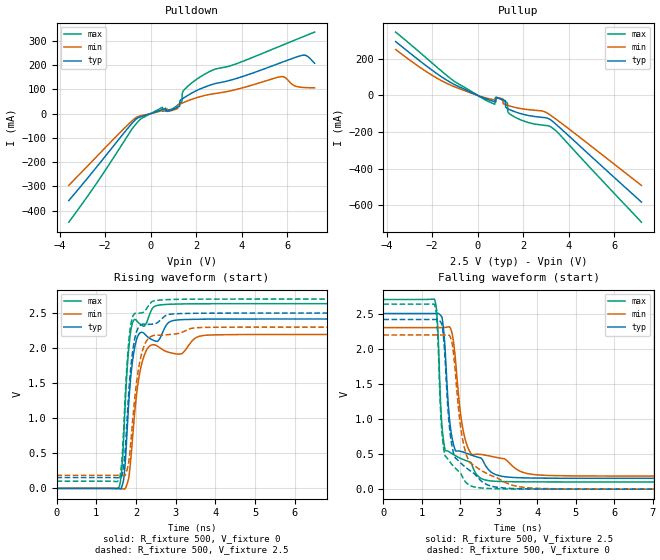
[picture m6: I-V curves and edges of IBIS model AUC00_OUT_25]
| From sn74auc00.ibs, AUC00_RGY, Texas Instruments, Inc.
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[Model]   AUC00_OUT_25
Model_type  Output
Vref =   0
Rref =   500
Cref =   30p
Vmeas =   1.25
| variable   typ   min   max
C_comp   7.46pF   0.24pF   23.67pF
| C_pullup   8.38pF   0.24pF   23.67pF
| C_pulldown   6.55pF   1.87pF   15.80pF
[Temperature Range]   40   100   -40
| Ambient temperature   25   85   -40
[Voltage range]   2.5   2.3   2.7
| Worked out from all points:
|   slope of the pulldown table from 0 to 0.375 V, typ, clamps not added: 30.9 ohm
|   slope of the pullup table from 0 to 0.375 V, typ, clamps not added: 19.2 ohm
|   rising waveform, R_fixture 500, V_fixture 0: 20-80 % time 201ps typ, 264ps min, 165ps max; typ from 0 V to 2.42 V
|   falling waveform, R_fixture 500, V_fixture 2.5: 20-80 % time 229ps typ, 316ps min, 160ps max; typ from 2.5 V to 0.154 V
|   rising waveform, R_fixture 500, V_fixture 2.5: 20-80 % time 198ps typ, 262ps min, 164ps max; typ from 0.154 V to 2.5 V
|   falling waveform, R_fixture 500, V_fixture 0: 20-80 % time 244ps typ, 338ps min, 162ps max; typ from 2.42 V to 0 V
[Pulldown]
| AUC00_OUT_25
|   Voltage   I(typ)   I(min)   I(max)
-3.6V     -358mA     -295.2mA   -447mA
-445mV    -13.39mA   -9.086mA   -23.04mA
515mV     17.02mA    12.57mA    25.99mA
1.025V    18.9mA     15.4mA     23.61mA
1.27V     30.1mA     38.43mA    41.47mA
1.37V     59.42mA    42.49mA    49.07mA
1.395V    60.94mA    43.5mA     85.27mA
1.48V     66.06mA    46.86mA    98.94mA
2.545V    115mA      77.99mA    170.9mA
5.695V    208.5mA    151.5mA    277.9mA
6.74V     240.5mA    107.2mA    317.9mA
7.2V      207mA      105.9mA    335.2mA
[Pullup]
| AUC00_OUT_25
|   Voltage   I(typ)   I(min)   I(max)
-3.6V     293.6mA    250.5mA    345.5mA
-960mV    55.5mA     44.14mA    71.53mA
730mV     -33.82mA   -24.42mA   -47.21mA
760mV     -34.84mA   -25.13mA   -47.16mA
770mV     -35.18mA   -25.36mA   -13.07mA
1.115V    -23.95mA   -20.34mA   -27.78mA
1.215V    -28.93mA   -50.57mA   -34.8mA
1.295V    -71.17mA   -53.86mA   -40.35mA
1.345V    -74.43mA   -55.82mA   -93.46mA
1.755V    -94.55mA   -68.88mA   -126.2mA
3.31V     -143.6mA   -118mA     -180.5mA
7.2V      -582.9mA   -492mA     -692.7mA
[Ramp]
| AUC00_OUT_25
| variable   typ   min   max
dV/dt_r   1.45/2.03E-10   1.32/2.65E-10   1.59/1.67E-10
dV/dt_f   1.41/2.30E-10   1.28/3.18E-10   1.56/1.62E-10
R_load = 500
[Rising Waveform]
| AUC00_OUT_25
R_fixture =   500
C_fixture =   0
L_fixture =   0
V_fixture =   0
V_fixture_min = 0
V_fixture_max = 0
|   Time   V(typ)   V(min)   V(max)
0s        9.791nV    28.67nV    1.858nV
1.58ns    -4.665mV   -935.2uV   22.55mV
1.645ns   24.84mV    -4.208mV   265.2mV
1.705ns   198.3mV    -9.379mV   888.5mV
1.79ns    941.1mV    85.17mV    1.79V
1.89ns    1.699V     542.2mV    2.308V
2.145ns   2.226V     1.773V     2.328V
2.54ns    2.097V     2.03V      2.609V
3.26ns    2.408V     1.984V     2.631V
20ns      2.416V     2.195V     2.634V
[Falling Waveform]
| AUC00_OUT_25
R_fixture =   500
C_fixture =   0
L_fixture =   0
V_fixture =   2.5
V_fixture_min = 2.3
V_fixture_max = 2.7
|   Time   V(typ)   V(min)   V(max)
0s        2.5V       2.3V       2.7V
1.33ns    2.501V     2.3V       2.702V
1.4ns     2.502V     2.3V       2.419V
1.525ns   2.446V     2.3V       888.2mV
1.6ns     2.032V     2.303V     566.6mV
1.715ns   1.018V     2.312V     530.1mV
1.855ns   575.3mV    1.947V     481.9mV
2.15ns    513.1mV    664.7mV    406.1mV
2.67ns    322.8mV    482mV      127.7mV
20ns      154.5mV    186.3mV    102.6mV
[Rising Waveform]
| AUC00_OUT_25
R_fixture =   500
C_fixture =   0
L_fixture =   0
V_fixture =   2.5
V_fixture_min = 2.3
V_fixture_max = 2.7
|   Time   V(typ)   V(min)   V(max)
0s        154.5mV    186.3mV    102.6mV
1.58ns    151.3mV    185.4mV    127.1mV
1.645ns   186.5mV    183mV      385.7mV
1.7ns     348.6mV    180.7mV    951.5mV
1.79ns    1.109V     295.8mV    1.886V
1.88ns    1.775V     720.2mV    2.364V
1.985ns   2.173V     1.366V     2.497V
2.12ns    2.331V     1.865V     2.501V
2.46ns    2.345V     2.183V     2.675V
20ns      2.5V       2.3V       2.7V
[Falling Waveform]
| AUC00_OUT_25
R_fixture =   500
C_fixture =   0
L_fixture =   0
V_fixture =   0
V_fixture_min = 0
V_fixture_max = 0
|   Time   V(typ)   V(min)   V(max)
0s        2.416V     2.195V     2.634V
1.33ns    2.416V     2.195V     2.629V
1.39ns    2.415V     2.195V     2.414V
1.59ns    1.972V     2.195V     501.8mV
1.7ns     984.6mV    2.192V     409.3mV
1.82ns    522.2mV    1.946V     327.7mV
2.06ns    347.1mV    708.5mV    168.9mV
2.37ns    216.3mV    330.6mV    30.3mV
4.115ns   2.029mV    9.437mV    495.1uV
20ns      23.68uV    3.157uV    10.98uV
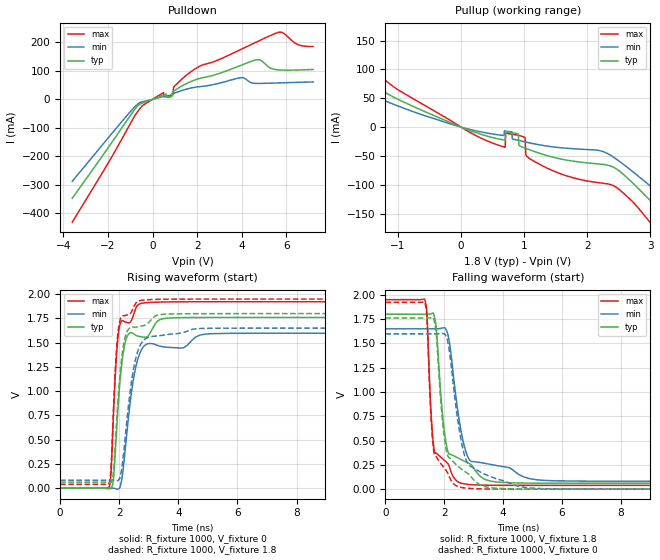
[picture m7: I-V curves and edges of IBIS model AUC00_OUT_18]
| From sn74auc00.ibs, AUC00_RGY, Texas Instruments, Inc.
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[Model]   AUC00_OUT_18
Model_type  Output
Vref =   0
Rref =   1000
Cref =   30p
Vmeas =   0.9
| variable   typ   min   max
C_comp   6.70pF   0.46pF   21.41pF
| C_pullup   7.16pF   1.06pF   21.41pF
| C_pulldown   6.24pF   0.46pF   15.47pF
[Temperature Range]   40   100   -40
| Ambient temperature   25   85   -40
[Voltage range]   1.8   1.65   1.95
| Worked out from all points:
|   slope of the pulldown table from 0 to 0.27 V, typ, clamps not added: 34.4 ohm
|   slope of the pullup table from 0 to 0.27 V, typ, clamps not added: 24.7 ohm
|   rising waveform, R_fixture 1000, V_fixture 0: 20-80 % time 278ps typ, 406ps min, 195ps max; typ from 0 V to 1.76 V
|   falling waveform, R_fixture 1000, V_fixture 1.8: 20-80 % time 326ps typ, 475ps min, 204ps max; typ from 1.8 V to 0.061 V
|   rising waveform, R_fixture 1000, V_fixture 1.8: 20-80 % time 274ps typ, 398ps min, 191ps max; typ from 0.061 V to 1.8 V
|   falling waveform, R_fixture 1000, V_fixture 0: 20-80 % time 335ps typ, 485ps min, 204ps max; typ from 1.76 V to 0 V
[Pulldown]
| AUC00_OUT_18
|   Voltage   I(typ)   I(min)   I(max)
-3.6V     -347.8mA   -287.9mA   -431.3mA
-830mV    -38.95mA   -28.95mA   -62.23mA
-405mV    -11.33mA   -7.446mA   -19.55mA
495mV     14.95mA    10.62mA    23.51mA
885mV     12.29mA    19.09mA    15.87mA
925mV     28.57mA    20.19mA    16.9mA
960mV     30.15mA    21.18mA    44.34mA
2.04V     71.84mA    43.97mA    113.3mA
3.92V     118.2mA    75.86mA    173.7mA
4.62V     138.3mA    56mA       199.9mA
5.58V     103.9mA    57.61mA    233.8mA
7.2V      105mA      61.31mA    185.3mA
[Pullup]
| AUC00_OUT_18
|   Voltage   I(typ)   I(min)   I(max)
-3.6V     267.6mA    221.5mA    318.7mA
-2.61V    174.3mA    138.3mA    219.8mA
-2.13V    131.5mA    101.8mA    171.7mA
110mV     -4.812mA   -3.244mA   -7.318mA
695mV     -22.64mA   -6.828mA   -34.84mA
705mV     -8.169mA   -6.943mA   -10.57mA
975mV     -34.74mA   -24.57mA   -16.33mA
1.11V     -40.27mA   -27.85mA   -56.21mA
2.25V     -64.64mA   -42.32mA   -97.32mA
3.1V      -138.7mA   -111.4mA   -179.7mA
3.92V     -231.1mA   -188.5mA   -290.4mA
7.2V      -598.2mA   -503.5mA   -721.3mA
[Ramp]
| AUC00_OUT_18
| variable   typ   min   max
dV/dt_r   1.06/2.80E-10   0.97/4.09E-10   1.16/1.97E-10
dV/dt_f   1.05/3.30E-10   0.95/4.81E-10   1.15/2.09E-10
R_load = 1000
[Rising Waveform]
| AUC00_OUT_18
R_fixture =   1000
C_fixture =   0
L_fixture =   0
V_fixture =   0
V_fixture_min = 0
V_fixture_max = 0
|   Time   V(typ)   V(min)   V(max)
0s        7.669nV    26.14nV    1.117nV
1.65ns    -2.946mV   534.2uV    7.49mV
1.725ns   -7.074mV   433.3uV    178.9mV
1.8ns     83.25mV    -1.437mV   725mV
1.995ns   989.9mV    -2.596mV   1.644V
2.25ns    1.552V     547mV      1.71V
2.475ns   1.594V     1.115V     1.78V
2.72ns    1.562V     1.407V     1.904V
3.81ns    1.756V     1.449V     1.921V
20ns      1.761V     1.597V     1.922V
[Falling Waveform]
| AUC00_OUT_18
R_fixture =   1000
C_fixture =   0
L_fixture =   0
V_fixture =   1.8
V_fixture_min = 1.65
V_fixture_max = 1.95
|   Time   V(typ)   V(min)   V(max)
0s        1.8V       1.65V      1.95V
1.335ns   1.8V       1.65V      1.953V
1.405ns   1.8V       1.65V      1.835V
1.55ns    1.804V     1.65V      799.3mV
1.665ns   1.776V     1.65V      393.8mV
2.075ns   452.5mV    1.635V     278.2mV
2.56ns    305.8mV    617.3mV    63.36mV
2.905ns   254.4mV    287.8mV    46.79mV
5.16ns    61.98mV    96.08mV    38.83mV
20ns      61.08mV    81.21mV    38.69mV
[Rising Waveform]
| AUC00_OUT_18
R_fixture =   1000
C_fixture =   0
L_fixture =   0
V_fixture =   1.8
V_fixture_min = 1.65
V_fixture_max = 1.95
|   Time   V(typ)   V(min)   V(max)
0s        61.05mV    81.2mV     38.68mV
1.645ns   58.83mV    81.58mV    44.63mV
1.72ns    55.19mV    81.49mV    206.1mV
1.795ns   144.3mV    79.97mV    736.9mV
1.895ns   605.8mV    74.57mV    1.368V
1.99ns    1.044V     89.37mV    1.679V
2.225ns   1.585V     598.9mV    1.783V
2.665ns   1.666V     1.445V     1.931V
4.775ns   1.8V       1.647V     1.95V
20ns      1.8V       1.65V      1.95V
[Falling Waveform]
| AUC00_OUT_18
R_fixture =   1000
C_fixture =   0
L_fixture =   0
V_fixture =   0
V_fixture_min = 0
V_fixture_max = 0
|   Time   V(typ)   V(min)   V(max)
0s        1.761V     1.597V     1.922V
1.335ns   1.761V     1.597V     1.923V
1.405ns   1.761V     1.597V     1.798V
1.545ns   1.763V     1.597V     779.4mV
1.655ns   1.74V      1.597V     371.1mV
2.05ns    436.2mV    1.582V     199.7mV
2.485ns   231.5mV    662.2mV    24.74mV
2.845ns   153.4mV    245mV      8.302mV
4.765ns   1.392mV    17.03mV    221.3uV
20ns      29.29uV    6.156uV    12.73uV
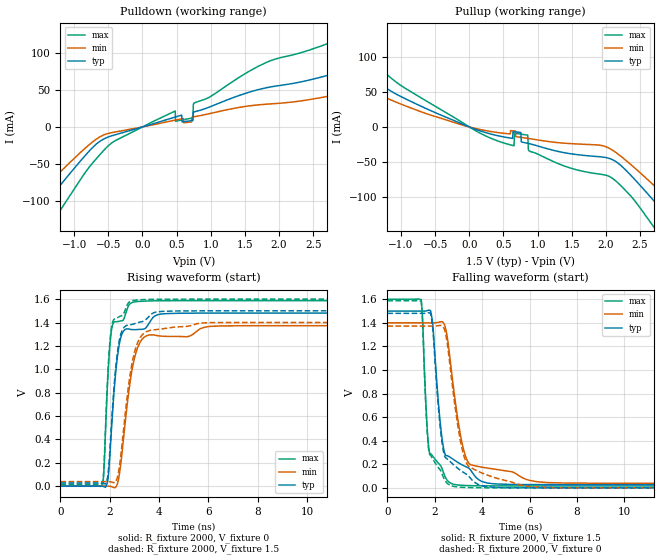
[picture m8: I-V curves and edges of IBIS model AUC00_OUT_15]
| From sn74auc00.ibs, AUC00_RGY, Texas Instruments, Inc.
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[Model]   AUC00_OUT_15
Model_type  Output
Vref =   0
Rref =   2000
Cref =   15p
Vmeas =   0.75
| variable   typ   min   max
C_comp   6.44pF   1.69pF   19.08pF
| C_pullup   6.16pF   1.69pF   19.08pF
| C_pulldown   6.72pF   3.62pF   15.24pF
[Temperature Range]   40   100   -40
| Ambient temperature   25   85   -40
[Voltage range]   1.5   1.4   1.6
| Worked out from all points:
|   slope of the pulldown table from 0 to 0.225 V, typ, clamps not added: 36.6 ohm
|   slope of the pullup table from 0 to 0.225 V, typ, clamps not added: 29.5 ohm
|   rising waveform, R_fixture 2000, V_fixture 0: 20-80 % time 349ps typ, 513ps min, 231ps max; typ from 0 V to 1.48 V
|   falling waveform, R_fixture 2000, V_fixture 1.5: 20-80 % time 406ps typ, 609ps min, 235ps max; typ from 1.5 V to 0.027 V
|   rising waveform, R_fixture 2000, V_fixture 1.5: 20-80 % time 345ps typ, 506ps min, 226ps max; typ from 0.027 V to 1.5 V
|   falling waveform, R_fixture 2000, V_fixture 0: 20-80 % time 404ps typ, 616ps min, 234ps max; typ from 1.48 V to 0 V
[Pulldown]
| AUC00_OUT_15
|   Voltage   I(typ)   I(min)   I(max)
-3.6V     -343.1mA   -285mA     -423.8mA
-2.105V   -179.1mA   -144.1mA   -232.5mA
-1.795V   -144.7mA   -115.1mA   -192.1mA
-1.395V   -99.91mA   -78.03mA   -138.7mA
-395mV    -10.45mA   -6.753mA   -18.28mA
480mV     13.33mA    9.224mA    21.44mA
485mV     13.46mA    9.315mA    7.619mA
735mV     8.725mA    13.4mA     12.06mA
755mV     20.22mA    13.7mA     32.02mA
1.69V     50.1mA     29.63mA    81.31mA
3.34V     86.08mA    49.98mA    134.3mA
7.2V      80.61mA    45.5mA     141.2mA
[Pullup]
| AUC00_OUT_15
|   Voltage   I(typ)   I(min)   I(max)
-3.6V     254.2mA    195.1mA    304.8mA
-2.88V    188mA      148.4mA    234.3mA
-2.315V   138mA      106.6mA    178.9mA
-1.915V   104.8mA    79.54mA    140.1mA
100mV     -3.652mA   -2.395mA   -5.808mA
650mV     -6.722mA   -5.655mA   -26.6mA
855mV     -23.23mA   -16.19mA   -11.7mA
885mV     -23.9mA    -16.64mA   -34.51mA
2.11V     -47.23mA   -33.88mA   -74mA
2.87V     -123.5mA   -98.22mA   -165.1mA
3.44V     -187.2mA   -151.2mA   -241.7mA
7.2V      -606.1mA   -510.5mA   -734.2mA
[Ramp]
| AUC00_OUT_15
| variable   typ   min   max
dV/dt_r   0.89/3.52E-10   0.83/5.21E-10   0.95/2.33E-10
dV/dt_f   0.89/4.12E-10   0.82/6.14E-10   0.95/2.38E-10
R_load = 2000
[Rising Waveform]
| AUC00_OUT_15
R_fixture =   2000
C_fixture =   0
L_fixture =   0
V_fixture =   0
V_fixture_min = 0
V_fixture_max = 0
|   Time   V(typ)   V(min)   V(max)
0s        7.042nV    26.32nV    876.9pV
1.72ns    -1.294mV   420.4uV    16.17mV
1.92ns    49.51mV    508.7uV    924.5mV
2.07ns    489.6mV    -4.173mV   1.335V
2.235ns   961.9mV    -9.8mV     1.407V
2.41ns    1.239V     132mV      1.412V
2.92ns    1.339V     1.015V     1.572V
3.465ns   1.355V     1.284V     1.583V
6.045ns   1.48V      1.367V     1.587V
20ns      1.481V     1.373V     1.587V
[Falling Waveform]
| AUC00_OUT_15
R_fixture =   2000
C_fixture =   0
L_fixture =   0
V_fixture =   1.5
V_fixture_min = 1.4
V_fixture_max = 1.6
|   Time   V(typ)   V(min)   V(max)
0s        1.5V       1.4V       1.6V
1.43ns    1.5V       1.4V       1.597V
1.675ns   1.503V     1.4V       527.6mV
1.82ns    1.504V     1.4V       290.2mV
2.325ns   395.5mV    1.408V     153.7mV
2.715ns   250.9mV    976.6mV    35.82mV
3.135ns   197.3mV    396.3mV    21.94mV
3.52ns    149mV      196.3mV    18.8mV
6.78ns    27.47mV    44.64mV    16.47mV
20ns      27.21mV    38.79mV    16.41mV
[Rising Waveform]
| AUC00_OUT_15
R_fixture =   2000
C_fixture =   0
L_fixture =   0
V_fixture =   1.5
V_fixture_min = 1.4
V_fixture_max = 1.6
|   Time   V(typ)   V(min)   V(max)
0s        27.17mV    38.78mV    16.4mV
1.72ns    25.93mV    39.11mV    35.78mV
1.92ns    87.65mV    39.13mV    954.5mV
2.065ns   521mV      35.32mV    1.353V
2.225ns   981.7mV    34.43mV    1.434V
2.385ns   1.245V     160.5mV    1.45V
2.845ns   1.381V     983mV      1.582V
3.415ns   1.418V     1.312V     1.597V
5.685ns   1.5V       1.395V     1.6V
20ns      1.5V       1.4V       1.6V
[Falling Waveform]
| AUC00_OUT_15
R_fixture =   2000
C_fixture =   0
L_fixture =   0
V_fixture =   0
V_fixture_min = 0
V_fixture_max = 0
|   Time   V(typ)   V(min)   V(max)
0s        1.481V     1.373V     1.587V
1.43ns    1.48V      1.373V     1.582V
1.675ns   1.483V     1.373V     501.6mV
1.82ns    1.48V      1.372V     276.6mV
2.31ns    381.3mV    1.377V     118.8mV
2.685ns   216.3mV    966.2mV    19mV
3.05ns    153.9mV    434mV      6.278mV
3.37ns    112mV      198.5mV    3.069mV
5.57ns    865.9uV    26.18mV    123.4uV
20ns      32uV       8.403uV    13.21uV
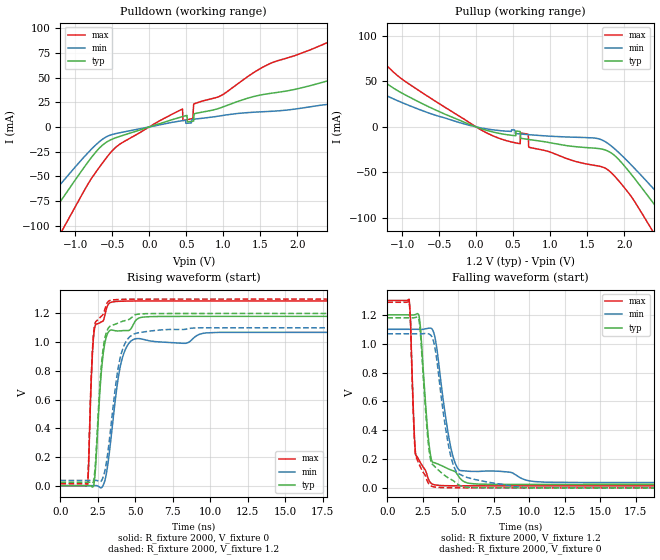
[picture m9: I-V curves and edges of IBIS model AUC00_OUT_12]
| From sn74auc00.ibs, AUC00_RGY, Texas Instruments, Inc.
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[Model]   AUC00_OUT_12
Model_type  Output
Vref =   0
Rref =   2000
Cref =   15p
Vmeas =   0.6
| variable   typ   min   max
C_comp   5.96pF   2.40pF   15.73pF
| C_pullup   5.54pF   2.40pF   15.73pF
| C_pulldown   6.39pF   4.24pF   14.99pF
[Temperature Range]   40   100   -40
| Ambient temperature   25   85   -40
[Voltage range]   1.2   1.1   1.3
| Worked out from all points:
|   slope of the pulldown table from 0 to 0.18 V, typ, clamps not added: 42.2 ohm
|   slope of the pullup table from 0 to 0.18 V, typ, clamps not added: 38.7 ohm
|   rising waveform, R_fixture 2000, V_fixture 0: 20-80 % time 479ps typ, 801ps min, 291ps max; typ from 0 V to 1.18 V
|   falling waveform, R_fixture 2000, V_fixture 1.2: 20-80 % time 558ps typ, 950ps min, 291ps max; typ from 1.2 V to 0.024 V
|   rising waveform, R_fixture 2000, V_fixture 1.2: 20-80 % time 470ps typ, 794ps min, 287ps max; typ from 0.024 V to 1.2 V
|   falling waveform, R_fixture 2000, V_fixture 0: 20-80 % time 558ps typ, 957ps min, 288ps max; typ from 1.18 V to 0 V
[Pulldown]
| AUC00_OUT_12
|   Voltage   I(typ)   I(min)   I(max)
-3.6V     -338.4mA   -281.3mA   -417.4mA
-1.805V   -141.9mA   -113.1mA   -187.6mA
-1.48V    -106.2mA   -83.26mA   -145.2mA
-1.22V    -77.61mA   -59.82mA   -110.7mA
-675mV    -21.44mA   -14.99mA   -40.91mA
-395mV    -9.496mA   -5.835mA   -17.3mA
450mV     10.5mA     6.398mA    18.24mA
590mV     5.848mA    7.731mA    8.546mA
605mV     12.96mA    7.861mA    23.36mA
2.86V     55.95mA    19.1mA     100.7mA
3.425V    44.58mA    20.08mA    119.3mA
7.2V      57.06mA    26.83mA    108mA
[Pullup]
| AUC00_OUT_12
|   Voltage   I(typ)   I(min)   I(max)
-3.6V     224.6mA    100.8mA    291.5mA
-2.7V     158.6mA    66.17mA    205.2mA
-2.11V    110.3mA    77.88mA    148.7mA
-1.68V    77.88mA    55.75mA    108.7mA
-1.025V   38.18mA    27.56mA    53.97mA
50mV      -1.427mA   -842.9uA   -2.489mA
700mV     -13.68mA   -8.451mA   -7.891mA
1.78V     -26.51mA   -18.1mA    -47.11mA
2.4V      -84.36mA   -68.15mA   -116.4mA
2.695V    -116.7mA   -94.78mA   -156.1mA
3.04V     -155mA     -126.6mA   -202.2mA
7.2V      -615.8mA   -521.7mA   -745.3mA
[Ramp]
| AUC00_OUT_12
| variable   typ   min   max
dV/dt_r   0.71/4.83E-10   0.65/8.12E-10   0.77/2.94E-10
dV/dt_f   0.71/5.66E-10   0.64/9.55E-10   0.78/2.97E-10
R_load = 2000
[Rising Waveform]
| AUC00_OUT_12
R_fixture =   2000
C_fixture =   0
L_fixture =   0
V_fixture =   0
V_fixture_min = 0
V_fixture_max = 0
|   Time   V(typ)   V(min)   V(max)
0s        6.587nV    27.93nV    705.3pV
1.82ns    351.6uV    221.4uV    10.91mV
2.06ns    -4.438mV   436.3uV    747.9mV
2.21ns    -3.617mV   634.8uV    1.039V
2.335ns   117.6mV    724.1uV    1.119V
2.805ns   877.3mV    -5.954mV   1.146V
3.335ns   1.084V     296.2mV    1.276V
4.045ns   1.079V     856.3mV    1.285V
4.995ns   1.148V     1.023V     1.287V
34.99ns   1.18V      1.069V     1.287V
[Falling Waveform]
| AUC00_OUT_12
R_fixture =   2000
C_fixture =   0
L_fixture =   0
V_fixture =   1.2
V_fixture_min = 1.1
V_fixture_max = 1.3
|   Time   V(typ)   V(min)   V(max)
0s        1.2V       1.1V       1.3V
1.53ns    1.2V       1.1V       1.309V
1.625ns   1.2V       1.1V       1.183V
1.94ns    1.201V     1.1V       302.8mV
2.21ns    1.202V     1.099V     197.1mV
2.875ns   361.2mV    1.107V     65.65mV
3.215ns   176.2mV    1.091V     24.35mV
4.415ns   126.5mV    307.7mV    14.61mV
5.125ns   65.93mV    120.2mV    14.13mV
34.99ns   24mV       36.64mV    13.87mV
[Rising Waveform]
| AUC00_OUT_12
R_fixture =   2000
C_fixture =   0
L_fixture =   0
V_fixture =   1.2
V_fixture_min = 1.1
V_fixture_max = 1.3
|   Time   V(typ)   V(min)   V(max)
0s        23.98mV    36.64mV    13.86mV
1.82ns    24.24mV    36.8mV     29.17mV
2.06ns    20.12mV    36.91mV    776.3mV
2.21ns    30.75mV    36.98mV    1.061V
2.785ns   899.2mV    44.04mV    1.187V
3.305ns   1.111V     356.5mV    1.291V
3.74ns    1.129V     746.2mV    1.297V
4.045ns   1.142V     916mV      1.298V
5.165ns   1.195V     1.065V     1.3V
34.99ns   1.2V       1.1V       1.3V
[Falling Waveform]
| AUC00_OUT_12
R_fixture =   2000
C_fixture =   0
L_fixture =   0
V_fixture =   0
V_fixture_min = 0
V_fixture_max = 0
|   Time   V(typ)   V(min)   V(max)
0s        1.18V      1.069V     1.287V
1.53ns    1.18V      1.069V     1.294V
1.625ns   1.18V      1.069V     1.16V
1.935ns   1.181V     1.069V     287.3mV
2.21ns    1.173V     1.069V     170.9mV
2.845ns   350.5mV    1.07V      40.59mV
3.14ns    166.3mV    1.048V     10.64mV
4.48ns    58.85mV    215.7mV    597.4uV
5.61ns    4.6mV      72.46mV    154.6uV
34.99ns   18.83uV    227nV      8.187uV
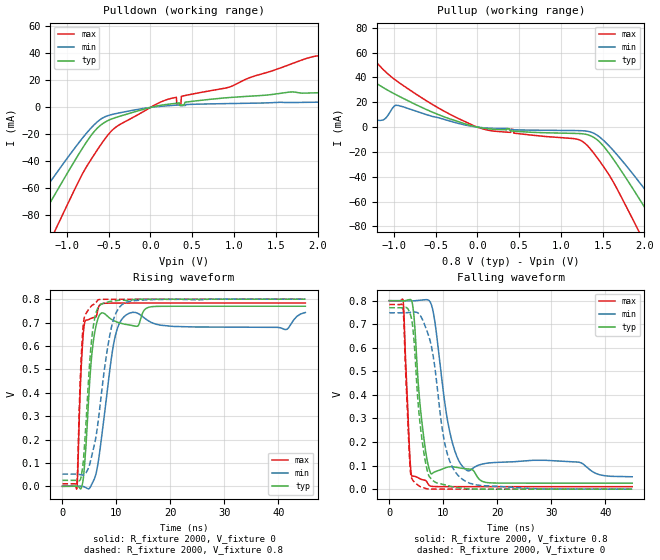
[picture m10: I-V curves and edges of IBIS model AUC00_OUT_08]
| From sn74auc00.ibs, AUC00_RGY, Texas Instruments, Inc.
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[Model]   AUC00_OUT_08
Model_type  Output
Vref =   0
Rref =   2000
Cref =   15p
Vmeas =   0.4
| variable   typ   min   max
C_comp   5.70pF   2.74pF   7.65pF
| C_pullup   5.16pF   2.74pF   7.65pF
| C_pulldown   6.24pF   5.46pF   6.86pF
[Temperature Range]   40   100   -40
| Ambient temperature   25   85   -40
[Voltage range]   0.8   0.8   0.8
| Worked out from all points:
|   slope of the pulldown table from 0 to 0.12 V, typ, clamps not added: 77.1 ohm
|   slope of the pullup table from 0 to 0.12 V, typ, clamps not added: 92.8 ohm
|   rising waveform, R_fixture 2000, V_fixture 0: 20-80 % time 1.41ns typ, 2.47ns min, 822ps max; typ from 0 V to 0.77 V
|   falling waveform, R_fixture 2000, V_fixture 0.8: 20-80 % time 1.77ns typ, 2.84ns min, 869ps max; typ from 0.8 V to 0.026 V
|   rising waveform, R_fixture 2000, V_fixture 0.8: 20-80 % time 1.39ns typ, 2.68ns min, 769ps max; typ from 0.025 V to 0.8 V
|   falling waveform, R_fixture 2000, V_fixture 0: 20-80 % time 1.78ns typ, 2.89ns min, 866ps max; typ from 0.77 V to 0 V
[Pulldown]
| AUC00_OUT_08
|   Voltage   I(typ)   I(min)   I(max)
-3.6V     -332.1mA   -277.7mA   -406.6mA
-1.635V   -117.5mA   -94.2mA    -155.3mA
-1.375V   -89.29mA   -70.69mA   -121.6mA
-1.155V   -65.62mA   -51.23mA   -92.89mA
-630mV    -14.96mA   -10.34mA   -30.86mA
-430mV    -7.788mA   -4.786mA   -15.33mA
-90mV     -1.494mA   -794.3uA   -3.292mA
210mV     2.329mA    1.254mA    6.027mA
365mV     1.692mA    1.285mA    2.781mA
1.98V     10.84mA    3.867mA    38.03mA
2.365V    11.74mA    4.199mA    33.49mA
7.2V      23.85mA    8.894mA    59.34mA
[Pullup]
| AUC00_OUT_08
|   Voltage   I(typ)   I(min)   I(max)
-3.6V     79.74mA    9.11mA     185.5mA
-3.08V    78.24mA    9.441mA    162.7mA
-1.56V    28.19mA    10.59mA    80.33mA
-1.305V   38.33mA    6.645mA    59.6mA
-1.13V    31.97mA    5.759mA    46.58mA
-975mV    26.17mA    17.62mA    37.64mA
-245mV    4.854mA    3.296mA    7.479mA
1.36V     -7.061mA   -3.966mA   -18.09mA
1.87V     -50.39mA   -38.35mA   -75.46mA
2.115V    -76.52mA   -59.57mA   -107.8mA
2.4V      -107.5mA   -85.08mA   -145.3mA
7.2V      -633.9mA   -537.3mA   -765.3mA
[Ramp]
| AUC00_OUT_08
| variable   typ   min   max
dV/dt_r   0.47/1.42E-09   0.45/2.51E-09   0.48/8.27E-10
dV/dt_f   0.47/1.77E-09   0.45/2.85E-09   0.48/8.75E-10
R_load = 2000
[Rising Waveform]
| AUC00_OUT_08
R_fixture =   2000
C_fixture =   0
L_fixture =   0
V_fixture =   0
V_fixture_min = 0
V_fixture_max = 0
|   Time   V(typ)   V(min)   V(max)
0s        8.079nV    45.62nV    527.9pV
2.69ns    488.7uV    558.9uV    -7.132mV
3.745ns   14.39mV    -229.7uV   615.1mV
5.505ns   576.1mV    11.84mV    719.9mV
6.995ns   736.8mV    163.3mV    777.7mV
9.585ns   707.5mV    620.6mV    783.5mV
11.87ns   691.8mV    733.7mV    783.6mV
16.54ns   768mV      699.8mV    783.7mV
41.36ns   770mV      670.1mV    783.8mV
45ns      770mV      743.2mV    783.8mV
[Falling Waveform]
| AUC00_OUT_08
R_fixture =   2000
C_fixture =   0
L_fixture =   0
V_fixture =   0.8
V_fixture_min = 0.8
V_fixture_max = 0.8
|   Time   V(typ)   V(min)   V(max)
0s        800mV      800mV      800mV
2.565ns   799.2mV    799.9mV    799.3mV
3.76ns    804.6mV    799.4mV    158.2mV
4.19ns    796.1mV    799.4mV    55.18mV
5.965ns   300mV      802.7mV    41.36mV
7.745ns   65.56mV    786mV      12.55mV
11.1ns    94.9mV     253.4mV    10.67mV
14.07ns   86.98mV    84.82mV    10.64mV
28.87ns   25.55mV    122.6mV    10.61mV
45ns      25.5mV     52.61mV    10.6mV
[Rising Waveform]
| AUC00_OUT_08
R_fixture =   2000
C_fixture =   0
L_fixture =   0
V_fixture =   0.8
V_fixture_min = 0.8
V_fixture_max = 0.8
|   Time   V(typ)   V(min)   V(max)
0s        25.46mV    52.25mV    10.6mV
2.66ns    25.16mV    51.95mV    9.06mV
2.81ns    24.65mV    51.53mV    75.48mV
3.46ns    40.2mV     49.16mV    541.2mV
4.01ns    148mV      49.1mV     715.8mV
5.36ns    616.1mV    123.3mV    770.7mV
6.575ns   763.2mV    269.4mV    796.6mV
9.01ns    791.3mV    672.6mV    799.8mV
11.38ns   795.7mV    782.2mV    799.9mV
45ns      800mV      800mV      800mV
[Falling Waveform]
| AUC00_OUT_08
R_fixture =   2000
C_fixture =   0
L_fixture =   0
V_fixture =   0
V_fixture_min = 0
V_fixture_max = 0
|   Time   V(typ)   V(min)   V(max)
0s        770mV      748.6mV    783.8mV
2.525ns   769.8mV    748.6mV    771.2mV
3.895ns   742mV      750.3mV    80.31mV
4.5ns     652.1mV    751.6mV    33.95mV
5.315ns   372.2mV    747.7mV    17.08mV
6.3ns     170.9mV    711.4mV    6.287mV
7.32ns    56.9mV     649.1mV    608.3uV
10.38ns   17.97mV    183.9mV    66.27uV
13.1ns    5.38mV     50.01mV    42.48uV
45ns      26.6uV     3.582uV    8.028uV
